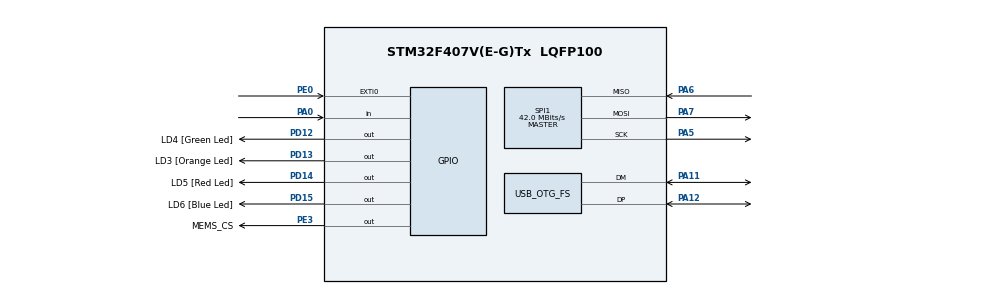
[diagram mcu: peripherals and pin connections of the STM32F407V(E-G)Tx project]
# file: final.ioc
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EdgeImpulse.jarvis.1.0.1.MachineLearningCcjarvisJjCore=true
Mcu.Family=STM32F4
Mcu.Name=STM32F407V(E-G)Tx
Mcu.Package=LQFP100
NVIC.EXTI0_IRQn=true\:0\:0\:false\:false\:true\:true\:true\:true
NVIC.OTG_FS_IRQn=true\:0\:0\:false\:false\:true\:false\:true\:true
NVIC.PriorityGroup=NVIC_PRIORITYGROUP_0
PA0-WKUP.Signal=GPIO_Input
PA11.Mode=Device_Only
PA11.Signal=USB_OTG_FS_DM
PA12.Mode=Device_Only
PA12.Signal=USB_OTG_FS_DP
PA5.Mode=Full_Duplex_Master
PA5.Signal=SPI1_SCK
PA6.Mode=Full_Duplex_Master
PA6.Signal=SPI1_MISO
PA7.Mode=Full_Duplex_Master
PA7.Signal=SPI1_MOSI
PD12.GPIO_Label=LD4 [Green Led]
PD12.GPIO_PuPd=GPIO_NOPULL
PD12.GPIO_Speed=GPIO_SPEED_FREQ_LOW
PD12.Signal=GPIO_Output
PD13.GPIO_Label=LD3 [Orange Led]
PD13.GPIO_PuPd=GPIO_NOPULL
PD13.GPIO_Speed=GPIO_SPEED_FREQ_LOW
PD13.Signal=GPIO_Output
PD14.GPIO_Label=LD5 [Red Led]
PD14.GPIO_PuPd=GPIO_NOPULL
PD14.GPIO_Speed=GPIO_SPEED_FREQ_LOW
PD14.Signal=GPIO_Output
PD15.GPIO_Label=LD6 [Blue Led]
PD15.GPIO_PuPd=GPIO_NOPULL
PD15.GPIO_Speed=GPIO_SPEED_FREQ_LOW
PD15.Signal=GPIO_Output
PE0.Signal=GPXTI0
PE3.GPIO_Label=MEMS_CS
PE3.Signal=GPIO_Output
PH0-OSC_IN.GPIO_Label=PH0-OSC_IN
PH0-OSC_IN.Mode=HSE-External-Oscillator
PH0-OSC_IN.Signal=RCC_OSC_IN
PH1-OSC_OUT.Mode=HSE-External-Oscillator
PH1-OSC_OUT.Signal=RCC_OSC_OUT
ProjectManager.HeapSize=0x200
ProjectManager.StackSize=0x400
ProjectManager.TargetToolchain=STM32CubeIDE
RCC.48MHZClocksFreq_Value=48000000
RCC.AHBFreq_Value=168000000
RCC.APB1CLKDivider=RCC_HCLK_DIV4
RCC.APB1Freq_Value=42000000
RCC.APB1TimFreq_Value=84000000
RCC.APB2CLKDivider=RCC_HCLK_DIV2
RCC.APB2Freq_Value=84000000
RCC.APB2TimFreq_Value=168000000
RCC.CortexFreq_Value=168000000
RCC.HCLKFreq_Value=168000000
RCC.HSE_VALUE=8000000
RCC.HSI_VALUE=16000000
RCC.LSE_VALUE=32768
RCC.PLLM=8
RCC.PLLN=336
RCC.PLLQ=7
RCC.SYSCLKFreq_VALUE=168000000
RCC.SYSCLKSource=RCC_SYSCLKSOURCE_PLLCLK
RCC.VCOOutputFreq_Value=336000000
SPI1.CalculateBaudRate=42.0 MBits/s
SPI1.Direction=SPI_DIRECTION_2LINES
SPI1.Mode=SPI_MODE_MASTER
SPI1.VirtualType=VM_MASTER
USB_DEVICE.CLASS_NAME_FS=CDC
USB_DEVICE.VirtualMode-CDC_FS=Cdc
USB_DEVICE.VirtualModeFS=Cdc_FS
USB_OTG_FS.VirtualMode=Device_Only
VP_CRC_VS_CRC.Mode=CRC_Activate
VP_EdgeImpulse.jarvis_VS_jarvisJjMachineLearning_1.0.1_1.0.1.Mode=jarvisJjMachineLearning
VP_USB_DEVICE_VS_USB_DEVICE_CDC_FS.Mode=CDC_FS
board=STM32F407G-DISC1

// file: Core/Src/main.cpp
/* USER CODE BEGIN Header */
/**
  ******************************************************************************
  * @file           : main.c
  * @brief          : Main program body
  ******************************************************************************
  * @attention
  *
  * Copyright (c) 2022 STMicroelectronics.
  * All rights reserved.
  *
  * This software is licensed under terms that can be found in the LICENSE file
  * in the root directory of this software component.
  * If no LICENSE file comes with this software, it is provided AS-IS.
  *
  ******************************************************************************
  */
/* USER CODE END Header */
#include "main.h"
#include "usb_device.h"

/* USER CODE BEGIN Includes */
#include "MY_LIS3DSH.h"
#include "usbd_cdc_if.h"
#include "string.h"
#include <stdio.h>
#include <stdarg.h>
#include "edge-impulse-sdk/classifier/ei_run_classifier.h"
/* USER CODE END Includes */

CRC_HandleTypeDef hcrc;

SPI_HandleTypeDef hspi1;

/* USER CODE BEGIN PV */
/* Private variables ---------------------------------------------------------*/
void vprint(const char *fmt, va_list argp)
{
    char string[200];
    if(0 < vsprintf(string, fmt, argp)) // build string
    {
        //HAL_UART_Transmit(&huart1, (uint8_t*)string, strlen(string), 0xffffff); // send message via UART
    	 CDC_Transmit_FS((uint8_t*)string, strlen(string));
    }
}

void ei_printf(const char *format, ...) {
    va_list myargs;
    va_start(myargs, format);
    vprint(format, myargs);
    va_end(myargs);
}
using namespace ei;

static float features[EI_CLASSIFIER_DSP_INPUT_FRAME_SIZE] = { 0.0 };

int get_feature_data(size_t offset, size_t length, float *out_ptr) {
    memcpy(out_ptr, features + offset, length * sizeof(float));
    return 0;
}
/* USER CODE END PV */

void SystemClock_Config(void);
static void MX_GPIO_Init(void);
static void MX_SPI1_Init(void);
static void MX_CRC_Init(void);
/* USER CODE BEGIN PFP */
/* Private function prototypes -----------------------------------------------*/

/* USER CODE END PFP */

/* USER CODE BEGIN 0 */

LIS3DSH_DataScaled myData;
char A[50];
int i=0;
uint8_t drdyFlag=0;
char charbuff[50];
int pressed=0;

using namespace std;
bool featuresarrayisready=false;
int countt=0;

/* USER CODE END 0 */

int main(void)
{
  /* USER CODE BEGIN 1 */
	LIS3DSH_InitTypeDef myAccConfigDef;
  /* USER CODE END 1 */

  /* MCU Configuration--------------------------------------------------------*/

  /* Reset of all peripherals, Initializes the Flash interface and the Systick. */
  HAL_Init();

  /* Configure the system clock */
  SystemClock_Config();

  /* Initialize all configured peripherals */
  MX_GPIO_Init();
  MX_SPI1_Init();
  MX_USB_DEVICE_Init();
  MX_CRC_Init();
  /* USER CODE BEGIN 2 */
	myAccConfigDef.dataRate = LIS3DSH_DATARATE_800;
	myAccConfigDef.fullScale = LIS3DSH_FULLSCALE_4;
	myAccConfigDef.enableAxes = LIS3DSH_XYZ_ENABLE;
	myAccConfigDef.interruptEnable = true;
	//myAccConfigDef.antiAliasingBW = LIS3DSH_FILTER_BW_50;
	LIS3DSH_Init(&hspi1, &myAccConfigDef);

	LIS3DSH_X_calibrate(-1000.0, 980.0);
	LIS3DSH_Y_calibrate(-1020.0, 1040.0);
	LIS3DSH_Z_calibrate(-920.0, 1040.0);
	signal_t signal;
	  	signal.total_length = sizeof(features) / sizeof(features[0]);
	  	signal.get_data = &get_feature_data;
  /* USER CODE END 2 */

  /* Infinite loop */
  while (1)
  {

    /* USER CODE BEGIN 3 */
	  for(;featuresarrayisready==false;)//arrayin tamamını doldurup doldurmadığını check ediyo
		{
		  	if(drdyFlag==1){ //data geldiyse 1 oluyor
		  		drdyFlag=0; // data işleniyorsa 0 oluyor
		  		myData = LIS3DSH_GetDataScaled(); // x-y-z datalarını alıyorum
		  		  	features[3*countt]=myData.x;// x değerini array e atıyorum
		  		  	features[3*countt+1]=myData.y; // y değerini array e atıyorum
		  		  	features[3*countt+2]=myData.z;// z değerini array e atıyorum
		  		  	countt++;
			  if(countt==EI_CLASSIFIER_RAW_SAMPLE_COUNT){ // array dolduysa başa gel baştan başla
						countt=0; // erişmek istediğim datanın değerini veriyorum
						featuresarrayisready=true;
					}
			HAL_GPIO_TogglePin(GPIOD, GPIO_PIN_12);

		  	}

		}
	  ei_impulse_result_t result = { 0 };
	  	      EI_IMPULSE_ERROR res = run_classifier(&signal, &result, true);
	  	      ei_printf("run_classifier returned: %d\n", res);

	  	      ei_printf("Predictions (DSP: %d ms., Classification: %d ms., Anomaly: %d ms.): \n",
	  	          result.timing.dsp, result.timing.classification, result.timing.anomaly);

	  	      // print the predictions
	  	      ei_printf("[");
	  	      for (size_t ix = 0; ix < EI_CLASSIFIER_LABEL_COUNT; ix++) {
	  	    	  ei_printf_float(result.classification[ix].value);
	  	  #if EI_CLASSIFIER_HAS_ANOMALY == 1
	  	          ei_printf(", ");
	  	  #else
	  	          if (ix != EI_CLASSIFIER_LABEL_COUNT - 1) {
	  	              ei_printf(", ");
	  	          }
	  	  #endif
	  	      }
	  	  #if EI_CLASSIFIER_HAS_ANOMALY == 1
	  	      ei_printf_float(result.anomaly);
	  	  #endif
	  	      ei_printf("]\n\n\n");

	  //memset(features, 0.0, EI_CLASSIFIER_DSP_INPUT_FRAME_SIZE);
	  HAL_Delay(1500);
	  featuresarrayisready=false;

  }
  /* USER CODE END 3 */
}

void SystemClock_Config(void)
{
  RCC_OscInitTypeDef RCC_OscInitStruct = {0};
  RCC_ClkInitTypeDef RCC_ClkInitStruct = {0};

  /** Configure the main internal regulator output voltage
  */
  __HAL_RCC_PWR_CLK_ENABLE();
  __HAL_PWR_VOLTAGESCALING_CONFIG(PWR_REGULATOR_VOLTAGE_SCALE1);

  /** Initializes the RCC Oscillators according to the specified parameters
  * in the RCC_OscInitTypeDef structure.
  */
  RCC_OscInitStruct.OscillatorType = RCC_OSCILLATORTYPE_HSI|RCC_OSCILLATORTYPE_HSE;
  RCC_OscInitStruct.HSEState = RCC_HSE_ON;
  RCC_OscInitStruct.HSIState = RCC_HSI_ON;
  RCC_OscInitStruct.HSICalibrationValue = RCC_HSICALIBRATION_DEFAULT;
  RCC_OscInitStruct.PLL.PLLState = RCC_PLL_ON;
  RCC_OscInitStruct.PLL.PLLSource = RCC_PLLSOURCE_HSE;
  RCC_OscInitStruct.PLL.PLLM = 4;
  RCC_OscInitStruct.PLL.PLLN = 72;
  RCC_OscInitStruct.PLL.PLLP = RCC_PLLP_DIV2;
  RCC_OscInitStruct.PLL.PLLQ = 3;
  if (HAL_RCC_OscConfig(&RCC_OscInitStruct) != HAL_OK)
  {
    Error_Handler();
  }

  /** Initializes the CPU, AHB and APB buses clocks
  */
  RCC_ClkInitStruct.ClockType = RCC_CLOCKTYPE_HCLK|RCC_CLOCKTYPE_SYSCLK
                              |RCC_CLOCKTYPE_PCLK1|RCC_CLOCKTYPE_PCLK2;
  RCC_ClkInitStruct.SYSCLKSource = RCC_SYSCLKSOURCE_HSI;
  RCC_ClkInitStruct.AHBCLKDivider = RCC_SYSCLK_DIV1;
  RCC_ClkInitStruct.APB1CLKDivider = RCC_HCLK_DIV1;
  RCC_ClkInitStruct.APB2CLKDivider = RCC_HCLK_DIV1;

  if (HAL_RCC_ClockConfig(&RCC_ClkInitStruct, FLASH_LATENCY_0) != HAL_OK)
  {
    Error_Handler();
  }
}

static void MX_CRC_Init(void)
{

  hcrc.Instance = CRC;
  if (HAL_CRC_Init(&hcrc) != HAL_OK)
  {
    Error_Handler();
  }

}

static void MX_SPI1_Init(void)
{

  /* SPI1 parameter configuration*/
  hspi1.Instance = SPI1;
  hspi1.Init.Mode = SPI_MODE_MASTER;
  hspi1.Init.Direction = SPI_DIRECTION_2LINES;
  hspi1.Init.DataSize = SPI_DATASIZE_8BIT;
  hspi1.Init.CLKPolarity = SPI_POLARITY_LOW;
  hspi1.Init.CLKPhase = SPI_PHASE_1EDGE;
  hspi1.Init.NSS = SPI_NSS_SOFT;
  hspi1.Init.BaudRatePrescaler = SPI_BAUDRATEPRESCALER_8;
  hspi1.Init.FirstBit = SPI_FIRSTBIT_MSB;
  hspi1.Init.TIMode = SPI_TIMODE_DISABLE;
  hspi1.Init.CRCCalculation = SPI_CRCCALCULATION_DISABLE;
  hspi1.Init.CRCPolynomial = 10;
  if (HAL_SPI_Init(&hspi1) != HAL_OK)
  {
    Error_Handler();
  }

}

static void MX_GPIO_Init(void)
{
  GPIO_InitTypeDef GPIO_InitStruct = {0};

  /* GPIO Ports Clock Enable */
  __HAL_RCC_GPIOE_CLK_ENABLE();
  __HAL_RCC_GPIOH_CLK_ENABLE();
  __HAL_RCC_GPIOA_CLK_ENABLE();
  __HAL_RCC_GPIOD_CLK_ENABLE();
  __HAL_RCC_GPIOB_CLK_ENABLE();

  /*Configure GPIO pin Output Level */
  HAL_GPIO_WritePin(MEMS_CS_GPIO_Port, MEMS_CS_Pin, GPIO_PIN_RESET);

  /*Configure GPIO pin Output Level */
  HAL_GPIO_WritePin(GPIOD, GPIO_PIN_12|GPIO_PIN_13|GPIO_PIN_14|GPIO_PIN_15, GPIO_PIN_RESET);

  /*Configure GPIO pin : MEMS_CS_Pin */
  GPIO_InitStruct.Pin = MEMS_CS_Pin;
  GPIO_InitStruct.Mode = GPIO_MODE_OUTPUT_PP;
  GPIO_InitStruct.Pull = GPIO_NOPULL;
  GPIO_InitStruct.Speed = GPIO_SPEED_FREQ_LOW;
  HAL_GPIO_Init(MEMS_CS_GPIO_Port, &GPIO_InitStruct);

  /*Configure GPIO pin : PA0 */
  GPIO_InitStruct.Pin = GPIO_PIN_0;
  GPIO_InitStruct.Mode = GPIO_MODE_INPUT;
  GPIO_InitStruct.Pull = GPIO_NOPULL;
  HAL_GPIO_Init(GPIOA, &GPIO_InitStruct);

  /*Configure GPIO pins : PD12 PD13 PD14 PD15 */
  GPIO_InitStruct.Pin = GPIO_PIN_12|GPIO_PIN_13|GPIO_PIN_14|GPIO_PIN_15;
  GPIO_InitStruct.Mode = GPIO_MODE_OUTPUT_PP;
  GPIO_InitStruct.Pull = GPIO_NOPULL;
  GPIO_InitStruct.Speed = GPIO_SPEED_FREQ_LOW;
  HAL_GPIO_Init(GPIOD, &GPIO_InitStruct);

  /*Configure GPIO pin : PE0 */
  GPIO_InitStruct.Pin = GPIO_PIN_0;
  GPIO_InitStruct.Mode = GPIO_MODE_IT_RISING;
  GPIO_InitStruct.Pull = GPIO_NOPULL;
  HAL_GPIO_Init(GPIOE, &GPIO_InitStruct);

  /* EXTI interrupt init*/
  HAL_NVIC_SetPriority(EXTI0_IRQn, 0, 0);
  HAL_NVIC_EnableIRQ(EXTI0_IRQn);

}

/* USER CODE BEGIN 4 */
void HAL_GPIO_EXTI_Callback(uint16_t GPIO_Pin)
{
  /* Prevent unused argument(s) compilation warning */
  UNUSED(GPIO_Pin);
  /* NOTE: This function Should not be modified, when the callback is needed,
           the HAL_GPIO_EXTI_Callback could be implemented in the user file
   */
 /* if(GPIO_Pin==GPIO_PIN_0){
  	  if(HAL_GPIO_ReadPin( GPIOA,GPIO_PIN_0)){*/
  drdyFlag = 1;
/*
  if(!featuresarrayisready){
  	myData = LIS3DSH_GetDataScaled();
  	features[3*countt]=myData.x;
  	features[3*countt+1]=myData.y;
  	features[3*countt+2]=myData.z;
	HAL_GPIO_TogglePin(GPIOD, GPIO_PIN_13);
	countt++;
	if(countt==EI_CLASSIFIER_RAW_SAMPLE_COUNT){
  		countt=0;
  		featuresarrayisready=true;
  	}
}*/
  	  /*}
  	   *
  	  else{
  		  if(pressed==1){
  		  i=0;
  		  pressed=0;
  		CDC_Transmit_FS("\n", strlen("\n"));
  		  }
  	  }
  }*/

}
/* USER CODE END 4 */

void Error_Handler(void)
{
  while(1)
  {
  }
}
